# Three metal layers and the cells a clock tree needs, for the clock tree
# synthesis tests.
VERSION 5.8 ;
BUSBITCHARS "[]" ;
DIVIDERCHAR "/" ;

UNITS
  DATABASE MICRONS 2000 ;
END UNITS

MANUFACTURINGGRID 0.005 ;

SITE core
  CLASS CORE ;
  SYMMETRY Y ;
  SIZE 0.19 BY 1.4 ;
END core

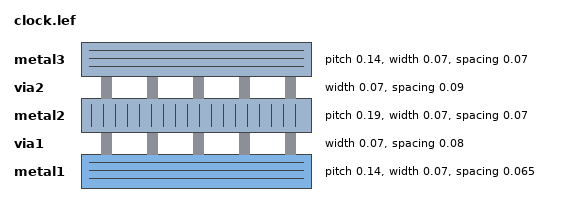
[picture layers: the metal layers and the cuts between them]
LAYER metal1
  TYPE ROUTING ;
  DIRECTION HORIZONTAL ;
  PITCH 0.14 ;
  WIDTH 0.07 ;
  SPACING 0.065 ;
END metal1

LAYER via1
  TYPE CUT ;
  WIDTH 0.07 ;
  SPACING 0.08 ;
END via1

LAYER metal2
  TYPE ROUTING ;
  DIRECTION VERTICAL ;
  PITCH 0.19 ;
  WIDTH 0.07 ;
  SPACING 0.07 ;
END metal2

LAYER via2
  TYPE CUT ;
  WIDTH 0.07 ;
  SPACING 0.09 ;
END via2

LAYER metal3
  TYPE ROUTING ;
  DIRECTION HORIZONTAL ;
  PITCH 0.14 ;
  WIDTH 0.07 ;
  SPACING 0.07 ;
END metal3

VIA via1_0 DEFAULT
  LAYER via1 ;
    RECT -0.035 -0.035 0.035 0.035 ;
  LAYER metal1 ;
    RECT -0.065 -0.035 0.065 0.035 ;
  LAYER metal2 ;
    RECT -0.035 -0.065 0.035 0.065 ;
END via1_0

VIA via2_0 DEFAULT
  LAYER via2 ;
    RECT -0.035 -0.035 0.035 0.035 ;
  LAYER metal2 ;
    RECT -0.035 -0.065 0.035 0.065 ;
  LAYER metal3 ;
    RECT -0.065 -0.035 0.065 0.035 ;
END via2_0

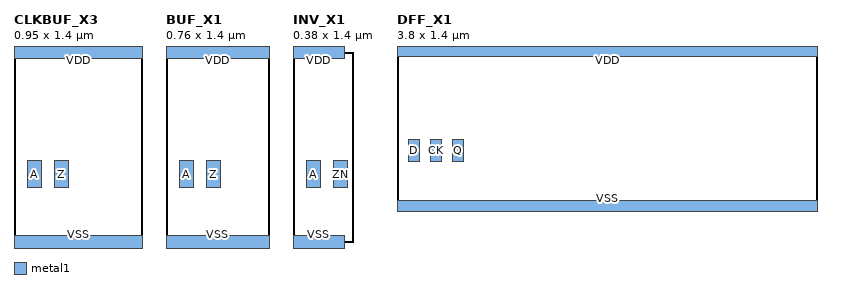
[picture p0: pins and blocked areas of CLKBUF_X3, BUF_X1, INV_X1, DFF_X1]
MACRO CLKBUF_X3
  CLASS CORE ;
  ORIGIN 0 0 ;
  SIZE 0.95 BY 1.4 ;
  SITE core ;
  PIN A
    DIRECTION INPUT ;
    USE SIGNAL ;
    PORT
      LAYER metal1 ;
        RECT 0.10 0.4 0.20 0.6 ;
    END
  END A
  PIN Z
    DIRECTION OUTPUT ;
    USE SIGNAL ;
    PORT
      LAYER metal1 ;
        RECT 0.30 0.4 0.40 0.6 ;
    END
  END Z
  PIN VDD
    DIRECTION INOUT ;
    USE POWER ;
    PORT
      LAYER metal1 ;
        RECT 0 1.35 0.95 1.45 ;
    END
  END VDD
  PIN VSS
    DIRECTION INOUT ;
    USE GROUND ;
    PORT
      LAYER metal1 ;
        RECT 0 -0.05 0.95 0.05 ;
    END
  END VSS
END CLKBUF_X3

MACRO BUF_X1
  CLASS CORE ;
  ORIGIN 0 0 ;
  SIZE 0.76 BY 1.4 ;
  SITE core ;
  PIN A
    DIRECTION INPUT ;
    USE SIGNAL ;
    PORT
      LAYER metal1 ;
        RECT 0.10 0.4 0.20 0.6 ;
    END
  END A
  PIN Z
    DIRECTION OUTPUT ;
    USE SIGNAL ;
    PORT
      LAYER metal1 ;
        RECT 0.30 0.4 0.40 0.6 ;
    END
  END Z
  PIN VDD
    DIRECTION INOUT ;
    USE POWER ;
    PORT
      LAYER metal1 ;
        RECT 0 1.35 0.76 1.45 ;
    END
  END VDD
  PIN VSS
    DIRECTION INOUT ;
    USE GROUND ;
    PORT
      LAYER metal1 ;
        RECT 0 -0.05 0.76 0.05 ;
    END
  END VSS
END BUF_X1

MACRO INV_X1
  CLASS CORE ;
  ORIGIN 0 0 ;
  SIZE 0.38 BY 1.4 ;
  SITE core ;
  PIN A
    DIRECTION INPUT ;
    USE SIGNAL ;
    PORT
      LAYER metal1 ;
        RECT 0.10 0.4 0.20 0.6 ;
    END
  END A
  PIN ZN
    DIRECTION OUTPUT ;
    USE SIGNAL ;
    PORT
      LAYER metal1 ;
        RECT 0.30 0.4 0.40 0.6 ;
    END
  END ZN
  PIN VDD
    DIRECTION INOUT ;
    USE POWER ;
    PORT
      LAYER metal1 ;
        RECT 0 1.35 0.38 1.45 ;
    END
  END VDD
  PIN VSS
    DIRECTION INOUT ;
    USE GROUND ;
    PORT
      LAYER metal1 ;
        RECT 0 -0.05 0.38 0.05 ;
    END
  END VSS
END INV_X1

MACRO DFF_X1
  CLASS CORE ;
  ORIGIN 0 0 ;
  SIZE 3.8 BY 1.4 ;
  SITE core ;
  PIN D
    DIRECTION INPUT ;
    USE SIGNAL ;
    PORT
      LAYER metal1 ;
        RECT 0.10 0.4 0.20 0.6 ;
    END
  END D
  PIN CK
    DIRECTION INPUT ;
    USE CLOCK ;
    PORT
      LAYER metal1 ;
        RECT 0.30 0.4 0.40 0.6 ;
    END
  END CK
  PIN Q
    DIRECTION OUTPUT ;
    USE SIGNAL ;
    PORT
      LAYER metal1 ;
        RECT 0.50 0.4 0.60 0.6 ;
    END
  END Q
  PIN VDD
    DIRECTION INOUT ;
    USE POWER ;
    PORT
      LAYER metal1 ;
        RECT 0 1.35 3.8 1.45 ;
    END
  END VDD
  PIN VSS
    DIRECTION INOUT ;
    USE GROUND ;
    PORT
      LAYER metal1 ;
        RECT 0 -0.05 3.8 0.05 ;
    END
  END VSS
END DFF_X1
END LIBRARY
